VERSION 5.7 ;
  NOWIREEXTENSIONATPIN ON ;
  DIVIDERCHAR "/" ;
  BUSBITCHARS "[]" ;
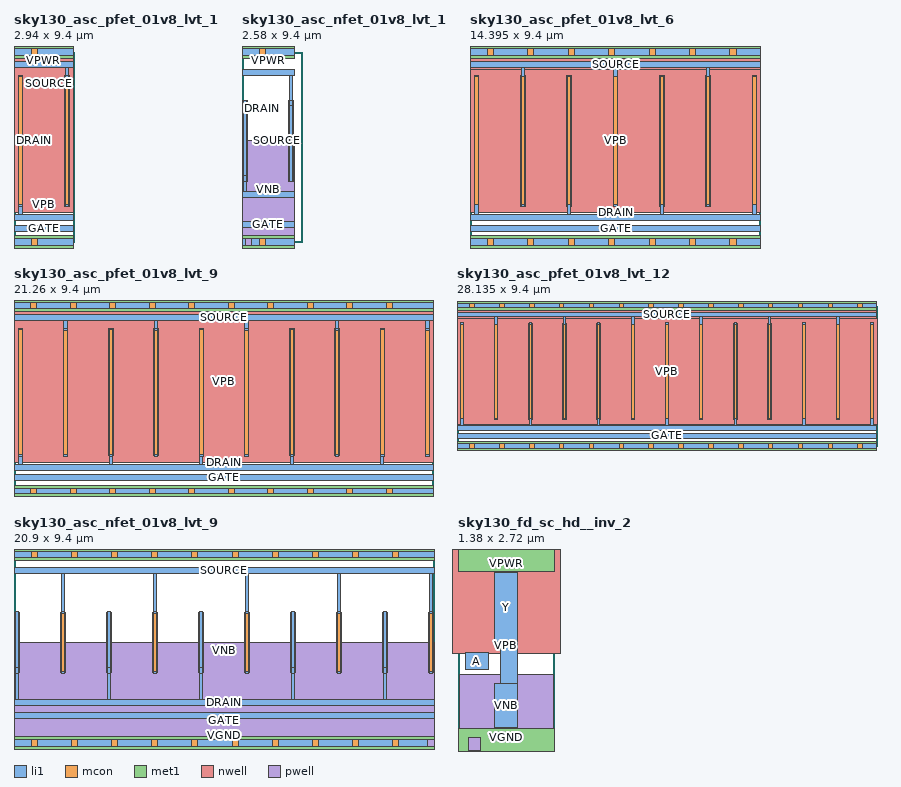
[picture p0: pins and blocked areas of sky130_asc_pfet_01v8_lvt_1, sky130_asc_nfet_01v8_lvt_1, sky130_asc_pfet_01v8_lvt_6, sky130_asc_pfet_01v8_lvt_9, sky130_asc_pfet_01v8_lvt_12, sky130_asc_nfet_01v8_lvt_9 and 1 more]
MACRO sky130_asc_pfet_01v8_lvt_1
  CLASS CORE ;
  FOREIGN sky130_asc_pfet_01v8_lvt_1 ;
  ORIGIN 0.000 0.000 ;
  SIZE 2.940 BY 9.400 ;
  SITE unitasc ;
  PIN GATE
    DIRECTION INOUT ;
    USE SIGNAL ;
    ANTENNAGATEAREA 12.900000 ;
    PORT
      LAYER li1 ;
        RECT 0.000 0.520 2.940 0.820 ;
    END
  END GATE
  PIN SOURCE
    DIRECTION INOUT ;
    USE SIGNAL ;
    ANTENNADIFFAREA 1.870500 ;
    PORT
      LAYER li1 ;
        RECT 0.000 8.650 2.940 8.950 ;
        RECT 2.525 8.245 2.695 8.650 ;
        RECT 2.525 8.130 2.700 8.245 ;
        RECT 2.530 1.755 2.700 8.130 ;
      LAYER mcon ;
        RECT 2.530 1.835 2.700 8.165 ;
      LAYER met1 ;
        RECT 2.500 1.775 2.730 8.225 ;
    END
  END SOURCE
  PIN DRAIN
    DIRECTION INOUT ;
    USE SIGNAL ;
    ANTENNADIFFAREA 1.870500 ;
    PORT
      LAYER li1 ;
        RECT 0.240 1.870 0.410 8.245 ;
        RECT 0.235 1.755 0.410 1.870 ;
        RECT 0.235 1.350 0.405 1.755 ;
        RECT 0.000 1.050 2.940 1.350 ;
      LAYER mcon ;
        RECT 0.240 1.835 0.410 8.165 ;
      LAYER met1 ;
        RECT 0.210 1.775 0.440 8.225 ;
    END
  END DRAIN
  PIN VPB
    DIRECTION INOUT ;
    USE POWER ;
    PORT
      LAYER nwell ;
        RECT 0.000 1.465 2.940 9.700 ;
    END
  END VPB
  PIN VPWR
    DIRECTION INOUT ;
    USE POWER ;
    SHAPE ABUTMENT ;
    PORT
      LAYER li1 ;
        RECT 0.000 9.250 2.940 9.550 ;
      LAYER mcon ;
        RECT 0.850 9.250 1.150 9.550 ;
      LAYER met1 ;
        RECT 0.000 9.100 2.940 9.700 ;
    END
  END VPWR
  PIN VGND
    DIRECTION INOUT ;
    USE GROUND ;
    SHAPE ABUTMENT ;
    PORT
      LAYER li1 ;
        RECT 0.000 -0.150 2.940 0.150 ;
      LAYER mcon ;
        RECT 0.850 -0.150 1.150 0.150 ;
      LAYER met1 ;
        RECT 0.000 -0.300 2.940 0.300 ;
    END
  END VGND
END sky130_asc_pfet_01v8_lvt_1

#--------EOF---------

MACRO sky130_asc_nfet_01v8_lvt_1
  CLASS CORE ;
  FOREIGN sky130_asc_nfet_01v8_lvt_1 ;
  ORIGIN 0.000 0.000 ;
  SIZE 2.580 BY 9.400 ;
  SITE unitasc ;
  PIN VNB
    DIRECTION INOUT ;
    USE POWER ;
    PORT
      LAYER pwell ;
        RECT 0.000 0.150 2.580 5.000 ;
        RECT 0.150 -0.150 0.450 0.150 ;
    END
  END VNB
  PIN GATE
    DIRECTION INOUT ;
    USE SIGNAL ;
    ANTENNAGATEAREA 8.000000 ;
    PORT
      LAYER li1 ;
        RECT 0.000 0.720 2.580 1.020 ;
    END
  END GATE
  PIN SOURCE
    DIRECTION INOUT ;
    USE SIGNAL ;
    ANTENNADIFFAREA 1.160000 ;
    PORT
      LAYER li1 ;
        RECT 0.000 8.250 2.580 8.550 ;
        RECT 2.345 7.020 2.515 8.250 ;
        RECT 2.345 6.730 2.520 7.020 ;
        RECT 2.350 2.980 2.520 6.730 ;
      LAYER mcon ;
        RECT 2.350 3.060 2.520 6.940 ;
      LAYER met1 ;
        RECT 2.320 3.000 2.550 7.000 ;
    END
  END SOURCE
  PIN DRAIN
    DIRECTION INOUT ;
    USE SIGNAL ;
    ANTENNADIFFAREA 1.160000 ;
    PORT
      LAYER li1 ;
        RECT 0.060 3.270 0.230 7.020 ;
        RECT 0.055 2.980 0.230 3.270 ;
        RECT 0.055 2.520 0.225 2.980 ;
        RECT 0.000 2.220 2.580 2.520 ;
      LAYER mcon ;
        RECT 0.060 3.060 0.230 6.940 ;
      LAYER met1 ;
        RECT 0.030 3.000 0.260 7.000 ;
    END
  END DRAIN
  PIN VPWR
    DIRECTION INOUT ;
    USE POWER ;
    PORT
      LAYER li1 ;
        RECT 0.000 9.250 2.580 9.550 ;
      LAYER mcon ;
        RECT 0.850 9.250 1.150 9.550 ;
      LAYER met1 ;
        RECT 0.000 9.100 2.580 9.700 ;
    END
  END VPWR
  PIN VGND
    DIRECTION INOUT ;
    USE GROUND ;
    PORT
      LAYER li1 ;
        RECT 0.000 -0.150 2.580 0.150 ;
      LAYER mcon ;
        RECT 0.850 -0.150 1.150 0.150 ;
      LAYER met1 ;
        RECT 0.000 -0.300 2.580 0.300 ;
    END
  END VGND
END sky130_asc_nfet_01v8_lvt_1

# -------------EOF--------------------

MACRO sky130_asc_pfet_01v8_lvt_6
  CLASS CORE ;
  FOREIGN sky130_asc_pfet_01v8_lvt_6 ;
  ORIGIN 0.000 0.000 ;
  SIZE 14.395 BY 9.400 ;
  SITE unitasc ;
  PIN GATE
    DIRECTION INOUT ;
    USE SIGNAL ;
    ANTENNAGATEAREA 77.400002 ;
    PORT
      LAYER li1 ;
        RECT 0.010 0.520 14.390 0.820 ;
    END
  END GATE
  PIN SOURCE
    DIRECTION INOUT ;
    USE SIGNAL ;
    ANTENNADIFFAREA 5.611500 ;
    PORT
      LAYER li1 ;
        RECT 0.010 8.650 14.390 8.950 ;
        RECT 2.535 1.755 2.705 8.650 ;
        RECT 7.115 1.755 7.285 8.650 ;
        RECT 11.695 1.755 11.865 8.650 ;
      LAYER mcon ;
        RECT 2.535 1.835 2.705 8.165 ;
        RECT 7.115 1.835 7.285 8.165 ;
        RECT 11.695 1.835 11.865 8.165 ;
      LAYER met1 ;
        RECT 2.505 1.775 2.735 8.225 ;
        RECT 7.085 1.775 7.315 8.225 ;
        RECT 11.665 1.775 11.895 8.225 ;
    END
  END SOURCE
  PIN DRAIN
    DIRECTION INOUT ;
    USE SIGNAL ;
    ANTENNADIFFAREA 7.482000 ;
    PORT
      LAYER li1 ;
        RECT 0.245 1.350 0.415 8.245 ;
        RECT 4.825 1.350 4.995 8.245 ;
        RECT 9.405 1.350 9.575 8.245 ;
        RECT 13.985 1.350 14.155 8.245 ;
        RECT 0.010 1.050 14.390 1.350 ;
      LAYER mcon ;
        RECT 0.245 1.835 0.415 8.165 ;
        RECT 4.825 1.835 4.995 8.165 ;
        RECT 9.405 1.835 9.575 8.165 ;
        RECT 13.985 1.835 14.155 8.165 ;
      LAYER met1 ;
        RECT 0.215 1.775 0.445 8.225 ;
        RECT 4.795 1.775 5.025 8.225 ;
        RECT 9.375 1.775 9.605 8.225 ;
        RECT 13.955 1.775 14.185 8.225 ;
    END
  END DRAIN
  PIN VPB
    DIRECTION INOUT ;
    USE POWER ;
    PORT
      LAYER nwell ;
        RECT 0.010 8.535 14.390 9.700 ;
        RECT 0.005 1.465 14.395 8.535 ;
    END
  END VPB
  PIN VPWR
    DIRECTION INOUT ;
    USE POWER ;
    PORT
      LAYER li1 ;
        RECT 0.010 9.250 14.390 9.550 ;
      LAYER mcon ;
        RECT 0.860 9.250 1.160 9.550 ;
        RECT 2.860 9.250 3.160 9.550 ;
        RECT 4.860 9.250 5.160 9.550 ;
        RECT 6.860 9.250 7.160 9.550 ;
        RECT 8.860 9.250 9.160 9.550 ;
        RECT 10.860 9.250 11.160 9.550 ;
        RECT 12.860 9.250 13.160 9.550 ;
      LAYER met1 ;
        RECT 0.010 9.100 14.390 9.700 ;
    END
  END VPWR
  PIN VGND
    DIRECTION INOUT ;
    USE GROUND ;
    PORT
      LAYER li1 ;
        RECT 0.010 -0.150 14.390 0.150 ;
      LAYER mcon ;
        RECT 0.860 -0.150 1.160 0.150 ;
        RECT 2.860 -0.150 3.160 0.150 ;
        RECT 4.860 -0.150 5.160 0.150 ;
        RECT 6.860 -0.150 7.160 0.150 ;
        RECT 8.860 -0.150 9.160 0.150 ;
        RECT 10.860 -0.150 11.160 0.150 ;
        RECT 12.860 -0.150 13.160 0.150 ;
      LAYER met1 ;
        RECT 0.010 -0.300 14.390 0.300 ;
    END
  END VGND
END sky130_asc_pfet_01v8_lvt_6

# -------------EOF--------------------

MACRO sky130_asc_pfet_01v8_lvt_9
  CLASS CORE ;
  FOREIGN sky130_asc_pfet_01v8_lvt_9 ;
  ORIGIN 0.000 0.000 ;
  SIZE 21.260 BY 9.400 ;
  SITE unitasc ;
  PIN GATE
    DIRECTION INOUT ;
    USE SIGNAL ;
    ANTENNAGATEAREA 116.099998 ;
    PORT
      LAYER li1 ;
        RECT 0.000 0.520 21.260 0.820 ;
    END
  END GATE
  PIN SOURCE
    DIRECTION INOUT ;
    USE SIGNAL ;
    ANTENNADIFFAREA 9.352500 ;
    PORT
      LAYER li1 ;
        RECT 0.000 8.650 21.260 8.950 ;
        RECT 2.525 8.245 2.695 8.650 ;
        RECT 7.105 8.245 7.275 8.650 ;
        RECT 11.685 8.245 11.855 8.650 ;
        RECT 16.265 8.245 16.435 8.650 ;
        RECT 20.845 8.245 21.015 8.650 ;
        RECT 2.525 8.130 2.700 8.245 ;
        RECT 7.105 8.130 7.280 8.245 ;
        RECT 11.685 8.130 11.860 8.245 ;
        RECT 16.265 8.130 16.440 8.245 ;
        RECT 20.845 8.130 21.020 8.245 ;
        RECT 2.530 1.755 2.700 8.130 ;
        RECT 7.110 1.755 7.280 8.130 ;
        RECT 11.690 1.755 11.860 8.130 ;
        RECT 16.270 1.755 16.440 8.130 ;
        RECT 20.850 1.755 21.020 8.130 ;
      LAYER mcon ;
        RECT 2.530 1.835 2.700 8.165 ;
        RECT 7.110 1.835 7.280 8.165 ;
        RECT 11.690 1.835 11.860 8.165 ;
        RECT 16.270 1.835 16.440 8.165 ;
        RECT 20.850 1.835 21.020 8.165 ;
      LAYER met1 ;
        RECT 2.500 1.775 2.730 8.225 ;
        RECT 7.080 1.775 7.310 8.225 ;
        RECT 11.660 1.775 11.890 8.225 ;
        RECT 16.240 1.775 16.470 8.225 ;
        RECT 20.820 1.775 21.050 8.225 ;
    END
  END SOURCE
  PIN DRAIN
    DIRECTION INOUT ;
    USE SIGNAL ;
    ANTENNADIFFAREA 9.352500 ;
    PORT
      LAYER li1 ;
        RECT 0.240 1.870 0.410 8.245 ;
        RECT 4.820 1.870 4.990 8.245 ;
        RECT 9.400 1.870 9.570 8.245 ;
        RECT 13.980 1.870 14.150 8.245 ;
        RECT 18.560 1.870 18.730 8.245 ;
        RECT 0.235 1.755 0.410 1.870 ;
        RECT 4.815 1.755 4.990 1.870 ;
        RECT 9.395 1.755 9.570 1.870 ;
        RECT 13.975 1.755 14.150 1.870 ;
        RECT 18.555 1.755 18.730 1.870 ;
        RECT 0.235 1.350 0.405 1.755 ;
        RECT 4.815 1.350 4.985 1.755 ;
        RECT 9.395 1.350 9.565 1.755 ;
        RECT 13.975 1.350 14.145 1.755 ;
        RECT 18.555 1.350 18.725 1.755 ;
        RECT 0.000 1.050 21.260 1.350 ;
      LAYER mcon ;
        RECT 0.240 1.835 0.410 8.165 ;
        RECT 4.820 1.835 4.990 8.165 ;
        RECT 9.400 1.835 9.570 8.165 ;
        RECT 13.980 1.835 14.150 8.165 ;
        RECT 18.560 1.835 18.730 8.165 ;
      LAYER met1 ;
        RECT 0.210 1.775 0.440 8.225 ;
        RECT 4.790 1.775 5.020 8.225 ;
        RECT 9.370 1.775 9.600 8.225 ;
        RECT 13.950 1.775 14.180 8.225 ;
        RECT 18.530 1.775 18.760 8.225 ;
    END
  END DRAIN
  PIN VPB
    DIRECTION INOUT ;
    USE POWER ;
    PORT
      LAYER nwell ;
        RECT 0.000 1.465 21.260 9.700 ;
    END
  END VPB
  PIN VPWR
    DIRECTION INOUT ;
    USE POWER ;
    PORT
      LAYER li1 ;
        RECT 0.000 9.250 21.260 9.550 ;
      LAYER mcon ;
        RECT 0.850 9.250 1.150 9.550 ;
        RECT 2.850 9.250 3.150 9.550 ;
        RECT 4.850 9.250 5.150 9.550 ;
        RECT 6.850 9.250 7.150 9.550 ;
        RECT 8.850 9.250 9.150 9.550 ;
        RECT 10.850 9.250 11.150 9.550 ;
        RECT 12.850 9.250 13.150 9.550 ;
        RECT 14.850 9.250 15.150 9.550 ;
        RECT 16.850 9.250 17.150 9.550 ;
        RECT 18.850 9.250 19.150 9.550 ;
      LAYER met1 ;
        RECT 0.000 9.100 21.260 9.700 ;
    END
  END VPWR
  PIN VGND
    DIRECTION INOUT ;
    USE GROUND ;
    PORT
      LAYER li1 ;
        RECT 0.000 -0.150 21.260 0.150 ;
      LAYER mcon ;
        RECT 0.850 -0.150 1.150 0.150 ;
        RECT 2.850 -0.150 3.150 0.150 ;
        RECT 4.850 -0.150 5.150 0.150 ;
        RECT 6.850 -0.150 7.150 0.150 ;
        RECT 8.850 -0.150 9.150 0.150 ;
        RECT 10.850 -0.150 11.150 0.150 ;
        RECT 12.850 -0.150 13.150 0.150 ;
        RECT 14.850 -0.150 15.150 0.150 ;
        RECT 16.850 -0.150 17.150 0.150 ;
        RECT 18.850 -0.150 19.150 0.150 ;
      LAYER met1 ;
        RECT 0.000 -0.300 21.260 0.300 ;
    END
  END VGND
END sky130_asc_pfet_01v8_lvt_9

# -------------EOF--------------------

MACRO sky130_asc_pfet_01v8_lvt_12
  CLASS CORE ;
  FOREIGN sky130_asc_pfet_01v8_lvt_12 ;
  ORIGIN 0.000 0.000 ;
  SIZE 28.135 BY 9.400 ;
  SITE unitasc ;
  PIN GATE
    DIRECTION INOUT ;
    USE SIGNAL ;
    ANTENNAGATEAREA 154.800003 ;
    PORT
      LAYER li1 ;
        RECT 0.010 0.520 28.130 0.820 ;
    END
  END GATE
  PIN SOURCE
    DIRECTION INOUT ;
    USE SIGNAL ;
    ANTENNADIFFAREA 11.223000 ;
    PORT
      LAYER li1 ;
        RECT 0.010 8.650 28.130 8.950 ;
        RECT 2.535 1.755 2.705 8.650 ;
        RECT 7.115 1.755 7.285 8.650 ;
        RECT 11.695 1.755 11.865 8.650 ;
        RECT 16.275 1.755 16.445 8.650 ;
        RECT 20.855 1.755 21.025 8.650 ;
        RECT 25.435 1.755 25.605 8.650 ;
      LAYER mcon ;
        RECT 2.535 1.835 2.705 8.165 ;
        RECT 7.115 1.835 7.285 8.165 ;
        RECT 11.695 1.835 11.865 8.165 ;
        RECT 16.275 1.835 16.445 8.165 ;
        RECT 20.855 1.835 21.025 8.165 ;
        RECT 25.435 1.835 25.605 8.165 ;
      LAYER met1 ;
        RECT 2.505 1.775 2.735 8.225 ;
        RECT 7.085 1.775 7.315 8.225 ;
        RECT 11.665 1.775 11.895 8.225 ;
        RECT 16.245 1.775 16.475 8.225 ;
        RECT 20.825 1.775 21.055 8.225 ;
        RECT 25.405 1.775 25.635 8.225 ;
    END
  END SOURCE
  PIN DRAIN
    DIRECTION INOUT ;
    USE SIGNAL ;
    ANTENNADIFFAREA 13.093500 ;
    PORT
      LAYER li1 ;
        RECT 0.245 1.350 0.415 8.245 ;
        RECT 4.825 1.350 4.995 8.245 ;
        RECT 9.405 1.350 9.575 8.245 ;
        RECT 13.985 1.350 14.155 8.245 ;
        RECT 18.565 1.350 18.735 8.245 ;
        RECT 23.145 1.350 23.315 8.245 ;
        RECT 27.725 1.350 27.895 8.245 ;
        RECT 0.010 1.050 28.130 1.350 ;
      LAYER mcon ;
        RECT 0.245 1.835 0.415 8.165 ;
        RECT 4.825 1.835 4.995 8.165 ;
        RECT 9.405 1.835 9.575 8.165 ;
        RECT 13.985 1.835 14.155 8.165 ;
        RECT 18.565 1.835 18.735 8.165 ;
        RECT 23.145 1.835 23.315 8.165 ;
        RECT 27.725 1.835 27.895 8.165 ;
      LAYER met1 ;
        RECT 0.215 1.775 0.445 8.225 ;
        RECT 4.795 1.775 5.025 8.225 ;
        RECT 9.375 1.775 9.605 8.225 ;
        RECT 13.955 1.775 14.185 8.225 ;
        RECT 18.535 1.775 18.765 8.225 ;
        RECT 23.115 1.775 23.345 8.225 ;
        RECT 27.695 1.775 27.925 8.225 ;
    END
  END DRAIN
  PIN VPB
    DIRECTION INOUT ;
    USE POWER ;
    PORT
      LAYER nwell ;
        RECT 0.010 8.535 28.130 9.700 ;
        RECT 0.005 1.465 28.135 8.535 ;
    END
  END VPB
  PIN VPWR
    DIRECTION INOUT ;
    USE POWER ;
    PORT
      LAYER li1 ;
        RECT 0.010 9.250 28.130 9.550 ;
      LAYER mcon ;
        RECT 0.860 9.250 1.160 9.550 ;
        RECT 2.860 9.250 3.160 9.550 ;
        RECT 4.860 9.250 5.160 9.550 ;
        RECT 6.860 9.250 7.160 9.550 ;
        RECT 8.860 9.250 9.160 9.550 ;
        RECT 10.860 9.250 11.160 9.550 ;
        RECT 12.860 9.250 13.160 9.550 ;
        RECT 14.860 9.250 15.160 9.550 ;
        RECT 16.860 9.250 17.160 9.550 ;
        RECT 18.860 9.250 19.160 9.550 ;
        RECT 20.860 9.250 21.160 9.550 ;
        RECT 22.860 9.250 23.160 9.550 ;
        RECT 24.860 9.250 25.160 9.550 ;
        RECT 26.860 9.250 27.160 9.550 ;
      LAYER met1 ;
        RECT 0.010 9.100 28.130 9.700 ;
    END
  END VPWR
  PIN VGND
    DIRECTION INOUT ;
    USE GROUND ;
    PORT
      LAYER li1 ;
        RECT 0.010 -0.150 28.130 0.150 ;
      LAYER mcon ;
        RECT 0.860 -0.150 1.160 0.150 ;
        RECT 2.860 -0.150 3.160 0.150 ;
        RECT 4.860 -0.150 5.160 0.150 ;
        RECT 6.860 -0.150 7.160 0.150 ;
        RECT 8.860 -0.150 9.160 0.150 ;
        RECT 10.860 -0.150 11.160 0.150 ;
        RECT 12.860 -0.150 13.160 0.150 ;
        RECT 14.860 -0.150 15.160 0.150 ;
        RECT 16.860 -0.150 17.160 0.150 ;
        RECT 18.860 -0.150 19.160 0.150 ;
        RECT 20.860 -0.150 21.160 0.150 ;
        RECT 22.860 -0.150 23.160 0.150 ;
        RECT 24.860 -0.150 25.160 0.150 ;
        RECT 26.860 -0.150 27.160 0.150 ;
      LAYER met1 ;
        RECT 0.010 -0.300 28.130 0.300 ;
    END
  END VGND
END sky130_asc_pfet_01v8_lvt_12

# -------------EOF--------------------

MACRO sky130_asc_nfet_01v8_lvt_9
  CLASS CORE ;
  FOREIGN sky130_asc_nfet_01v8_lvt_9 ;
  ORIGIN 0.000 0.000 ;
  SIZE 20.900 BY 9.400 ;
  SITE unitasc ;
  PIN GATE
    DIRECTION INOUT ;
    ANTENNAGATEAREA 54.000000 ;
    PORT
      LAYER li1 ;
        RECT 0.000 1.220 20.900 1.520 ;
    END
  END GATE
  PIN SOURCE
    DIRECTION INOUT ;
    ANTENNADIFFAREA 4.350000 ;
    PORT
      LAYER li1 ;
        RECT 0.000 8.450 20.900 8.750 ;
        RECT 2.345 6.520 2.515 8.450 ;
        RECT 6.925 6.520 7.095 8.450 ;
        RECT 11.505 6.520 11.675 8.450 ;
        RECT 16.085 6.520 16.255 8.450 ;
        RECT 20.665 6.520 20.835 8.450 ;
        RECT 2.345 6.430 2.520 6.520 ;
        RECT 6.925 6.430 7.100 6.520 ;
        RECT 11.505 6.430 11.680 6.520 ;
        RECT 16.085 6.430 16.260 6.520 ;
        RECT 20.665 6.430 20.840 6.520 ;
        RECT 2.350 3.480 2.520 6.430 ;
        RECT 6.930 3.480 7.100 6.430 ;
        RECT 11.510 3.480 11.680 6.430 ;
        RECT 16.090 3.480 16.260 6.430 ;
        RECT 20.670 3.480 20.840 6.430 ;
      LAYER mcon ;
        RECT 2.350 3.560 2.520 6.440 ;
        RECT 6.930 3.560 7.100 6.440 ;
        RECT 11.510 3.560 11.680 6.440 ;
        RECT 16.090 3.560 16.260 6.440 ;
        RECT 20.670 3.560 20.840 6.440 ;
      LAYER met1 ;
        RECT 2.320 3.500 2.550 6.500 ;
        RECT 6.900 3.500 7.130 6.500 ;
        RECT 11.480 3.500 11.710 6.500 ;
        RECT 16.060 3.500 16.290 6.500 ;
        RECT 20.640 3.500 20.870 6.500 ;
    END
  END SOURCE
  PIN DRAIN
    DIRECTION INOUT ;
    ANTENNADIFFAREA 4.350000 ;
    PORT
      LAYER li1 ;
        RECT 0.060 3.770 0.230 6.520 ;
        RECT 4.640 3.770 4.810 6.520 ;
        RECT 9.220 3.770 9.390 6.520 ;
        RECT 13.800 3.770 13.970 6.520 ;
        RECT 18.380 3.770 18.550 6.520 ;
        RECT 0.055 3.480 0.230 3.770 ;
        RECT 4.635 3.480 4.810 3.770 ;
        RECT 9.215 3.480 9.390 3.770 ;
        RECT 13.795 3.480 13.970 3.770 ;
        RECT 18.375 3.480 18.550 3.770 ;
        RECT 0.055 2.150 0.225 3.480 ;
        RECT 4.635 2.150 4.805 3.480 ;
        RECT 9.215 2.150 9.385 3.480 ;
        RECT 13.795 2.150 13.965 3.480 ;
        RECT 18.375 2.150 18.545 3.480 ;
        RECT 0.000 1.850 20.900 2.150 ;
      LAYER mcon ;
        RECT 0.060 3.560 0.230 6.440 ;
        RECT 4.640 3.560 4.810 6.440 ;
        RECT 9.220 3.560 9.390 6.440 ;
        RECT 13.800 3.560 13.970 6.440 ;
        RECT 18.380 3.560 18.550 6.440 ;
      LAYER met1 ;
        RECT 0.030 3.500 0.260 6.500 ;
        RECT 4.610 3.500 4.840 6.500 ;
        RECT 9.190 3.500 9.420 6.500 ;
        RECT 13.770 3.500 14.000 6.500 ;
        RECT 18.350 3.500 18.580 6.500 ;
    END
  END DRAIN
  PIN VNB
    DIRECTION INOUT ;
    USE GROUND ;
    PORT
      LAYER pwell ;
        RECT 0.000 0.150 20.900 5.000 ;
        RECT 20.600 -0.150 20.900 0.150 ;
    END
  END VNB
  PIN VPWR
    DIRECTION INOUT ;
    USE POWER ;
    PORT
      LAYER li1 ;
        RECT 0.000 9.250 20.900 9.550 ;
      LAYER mcon ;
        RECT 0.850 9.250 1.150 9.550 ;
        RECT 2.850 9.250 3.150 9.550 ;
        RECT 4.850 9.250 5.150 9.550 ;
        RECT 6.850 9.250 7.150 9.550 ;
        RECT 8.850 9.250 9.150 9.550 ;
        RECT 10.850 9.250 11.150 9.550 ;
        RECT 12.850 9.250 13.150 9.550 ;
        RECT 14.850 9.250 15.150 9.550 ;
        RECT 16.850 9.250 17.150 9.550 ;
        RECT 18.850 9.250 19.150 9.550 ;
      LAYER met1 ;
        RECT 0.000 9.100 20.900 9.700 ;
    END
  END VPWR
  PIN VGND
    DIRECTION INOUT ;
    USE GROUND ;
    PORT
      LAYER li1 ;
        RECT 0.000 -0.150 20.900 0.150 ;
      LAYER mcon ;
        RECT 0.850 -0.150 1.150 0.150 ;
        RECT 2.850 -0.150 3.150 0.150 ;
        RECT 4.850 -0.150 5.150 0.150 ;
        RECT 6.850 -0.150 7.150 0.150 ;
        RECT 8.850 -0.150 9.150 0.150 ;
        RECT 10.850 -0.150 11.150 0.150 ;
        RECT 12.850 -0.150 13.150 0.150 ;
        RECT 14.850 -0.150 15.150 0.150 ;
        RECT 16.850 -0.150 17.150 0.150 ;
        RECT 18.850 -0.150 19.150 0.150 ;
      LAYER met1 ;
        RECT 0.000 -0.300 20.900 0.300 ;
    END
  END VGND
END sky130_asc_nfet_01v8_lvt_9

# -------------EOF--------------------

MACRO sky130_fd_sc_hd__inv_2
  CLASS CORE ;
  FOREIGN sky130_fd_sc_hd__inv_2 ;
  ORIGIN 0.000 0.000 ;
  SIZE 1.380 BY 2.720 ;
  SYMMETRY X Y R90 ;
  SITE unithd ;
  PIN A
    DIRECTION INPUT ;
    USE SIGNAL ;
    ANTENNAGATEAREA 0.495000 ;
    PORT
      LAYER li1 ;
        RECT 0.105 1.075 0.435 1.325 ;
    END
  END A
  PIN VGND
    DIRECTION INOUT ;
    USE GROUND ;
    SHAPE ABUTMENT ;
    PORT
      LAYER met1 ;
        RECT 0.000 -0.240 1.380 0.240 ;
    END
  END VGND
  PIN VNB
    DIRECTION INOUT ;
    USE GROUND ;
    PORT
      LAYER pwell ;
        RECT 0.015 0.105 1.365 1.015 ;
        RECT 0.145 -0.085 0.315 0.105 ;
    END
  END VNB
  PIN VPB
    DIRECTION INOUT ;
    USE POWER ;
    PORT
      LAYER nwell ;
        RECT -0.190 1.305 1.570 2.910 ;
    END
  END VPB
  PIN VPWR
    DIRECTION INOUT ;
    USE POWER ;
    SHAPE ABUTMENT ;
    PORT
      LAYER met1 ;
        RECT 0.000 2.480 1.380 2.960 ;
    END
  END VPWR
  PIN Y
    DIRECTION OUTPUT ;
    USE SIGNAL ;
    ANTENNADIFFAREA 0.445500 ;
    PORT
      LAYER li1 ;
        RECT 0.525 1.485 0.855 2.465 ;
        RECT 0.605 0.885 0.855 1.485 ;
        RECT 0.525 0.255 0.855 0.885 ;
    END
  END Y
  OBS
      LAYER li1 ;
        RECT 0.000 2.635 1.380 2.805 ;
        RECT 0.125 1.495 0.355 2.635 ;
        RECT 1.025 1.495 1.235 2.635 ;
        RECT 0.125 0.085 0.355 0.905 ;
        RECT 1.025 0.085 1.235 0.905 ;
        RECT 0.000 -0.085 1.380 0.085 ;
      LAYER mcon ;
        RECT 0.145 2.635 0.315 2.805 ;
        RECT 0.605 2.635 0.775 2.805 ;
        RECT 1.065 2.635 1.235 2.805 ;
        RECT 0.145 -0.085 0.315 0.085 ;
        RECT 0.605 -0.085 0.775 0.085 ;
        RECT 1.065 -0.085 1.235 0.085 ;
  END
END sky130_fd_sc_hd__inv_2

END LIBRARY





